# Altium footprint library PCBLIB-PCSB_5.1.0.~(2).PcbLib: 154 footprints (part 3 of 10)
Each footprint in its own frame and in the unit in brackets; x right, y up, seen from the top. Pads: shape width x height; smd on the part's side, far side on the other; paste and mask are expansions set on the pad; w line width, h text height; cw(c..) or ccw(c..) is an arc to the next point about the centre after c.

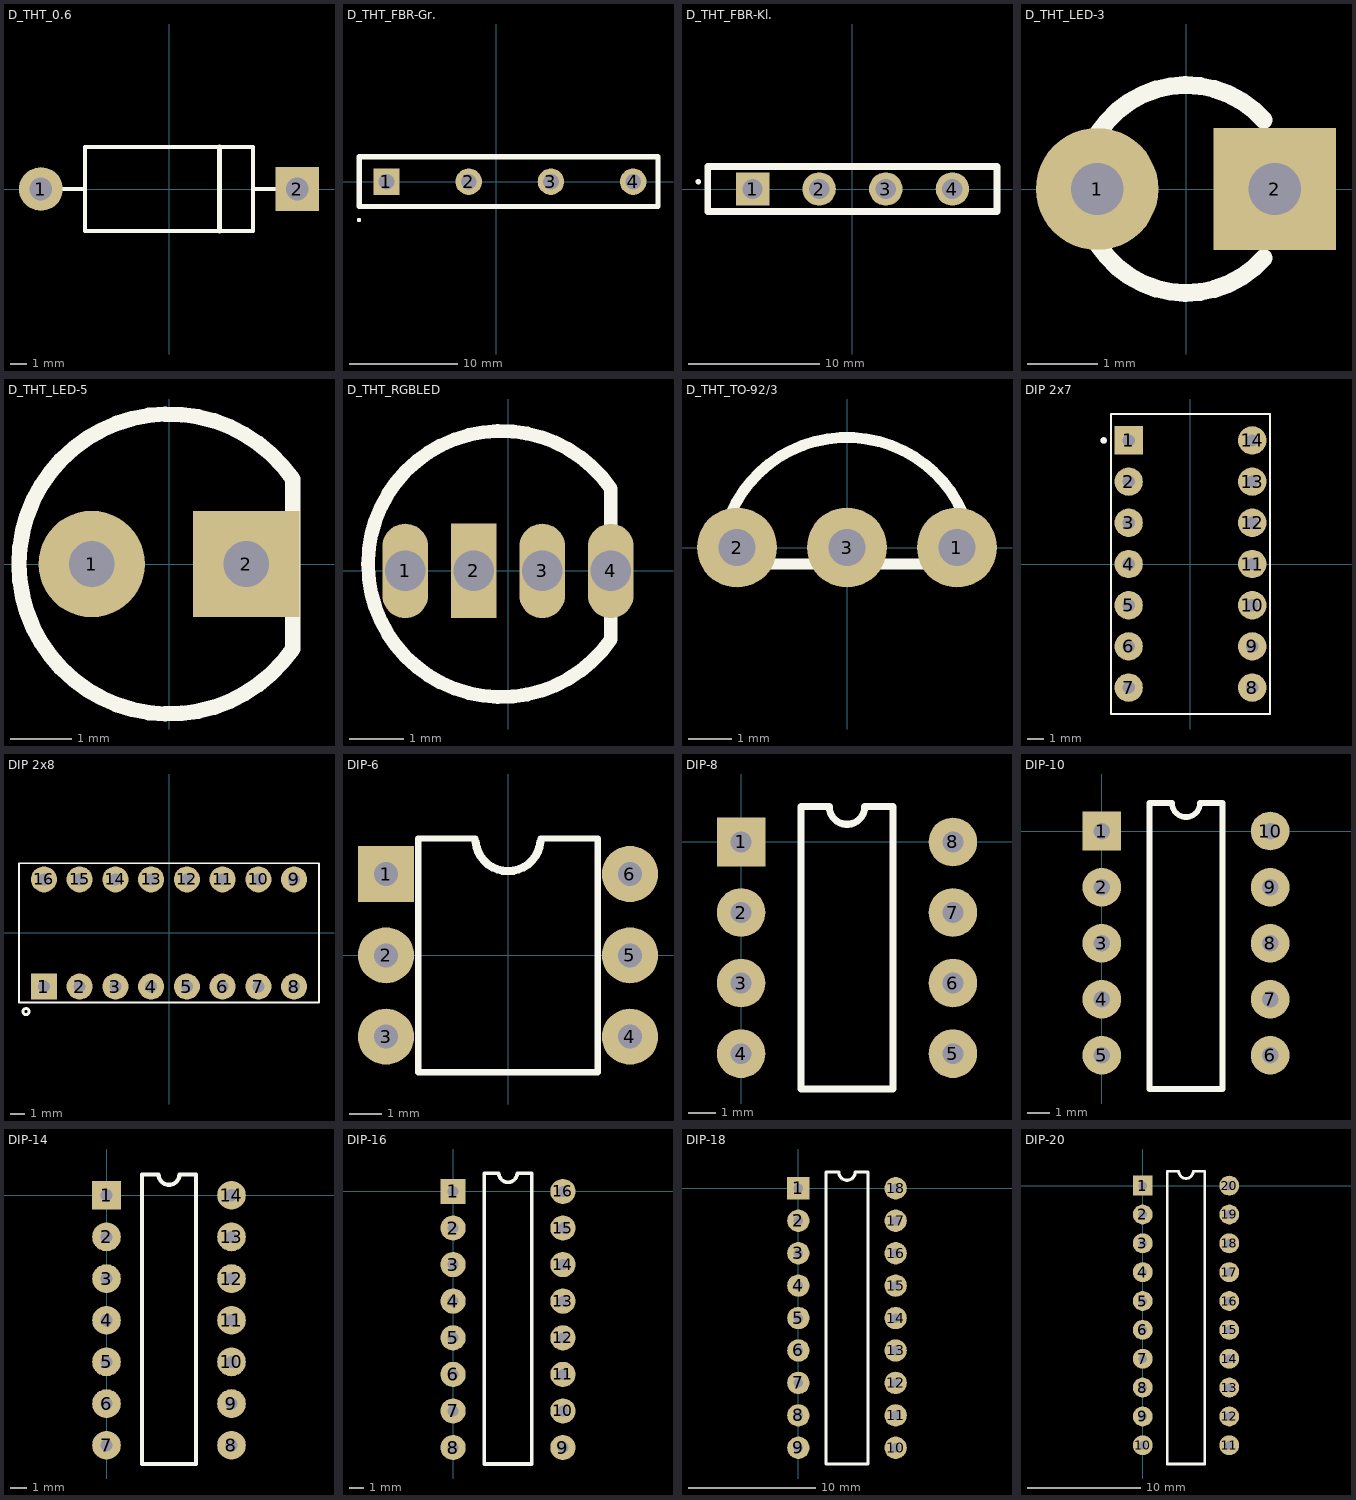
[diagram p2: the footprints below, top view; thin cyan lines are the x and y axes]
## D_THT_0.6 [mm] "LB-2024-04-17"
pads (2):
  round 2.6 hole 1.35: 1(-7.62,0)
  rect 2.6x2.6 hole 1.35: 2(7.62,0)
Top Overlay:
  lines w0.254: -7,0 -5,0 ; -5,-2.5 -5,2.5 5,2.5 5,-2.5 -4.89,-2.5 ; 5,0 7.016,0
  lines w0.3: 3,-2.5 3,2.5

## D_THT_FBR-Gr. [mm] "LB-2024-04-18"
height 23
pads (4):
  rect 2.45x2.45 hole 1.45: 1(-10.16,0)
  round 2.45 hole 1.45: 2(-2.54,0) 3(5.08,0) 4(12.7,0)
Top Overlay:
  circle w0.2: c-12.7,-3.556 r0.1
  lines w0.5: -12.7,-2.3 -12.7,2.3 15,2.3 15,-2.3 -12.7,-2.3

## D_THT_FBR-Kl. [mm] "LB-2024-04-18"
pads (4):
  rect 2.55x2.55 hole 1.55: 1(-7.62,0)
  round 2.55 hole 1.55: 2(-2.54,0) 3(2.54,0) 4(7.62,0)
Top Overlay:
  circle w0.2: c-11.76,0.56 r0.1
  lines w0.5: -9.095,1.715 -11.025,1.715 ; 9.095,1.715 11.025,1.715 ; -11.025,1.715 11.025,1.715 ; -11.025,1.715 -11.025,-1.715 11.025,-1.715 11.025,1.715
Mechanical 13:
  circle w0.2: c-11.76,0.56 r0.1

## D_THT_LED-3 [mm] "LB-2024-04-17"
pads (2):
  round 1.75 hole 0.75: 1(-1.27,0)
  rect 1.75x1.75 hole 0.75: 2(1.27,0)
Top Overlay:
  lines w0.254: 1.111,-0.988 cw(c0,0) 1.111,0.988 ; 1.397,-0.508 1.397,0.508

## D_THT_LED-5 [mm] "LB-2024-04-17"
pads (2):
  round 1.75 hole 0.75: 1(-1.27,0)
  rect 1.75x1.75 hole 0.75: 2(1.27,0)
Top Overlay:
  lines w0.254: 2.032,-1.397 cw(c0,0) 2.032,1.397 2.032,-1.397

## D_THT_RGBLED [mm] "LB-2024-04-17"
pads (4):
  oval 0.85x1.75 hole 0.75: 1(-1.905,0) 3(0.635,0) 4(1.905,0)
  rect 0.85x1.75 hole 0.75: 2(-0.635,0)
Top Overlay:
  lines w0.254: 1.905,-0.635 1.905,-1.27 cw(c-0.127,0.127) 1.905,1.524 1.905,0.635

## D_THT_TO-92/3 [mm] "LB-2024-04-19"
pads (3):
  round 1.85 hole 0.85: 1(2.54,0) 2(-2.54,0) 3(0,0)
Top Overlay:
  lines w0.254: -2.927,-0.381 cw(c-0.003,-0.381) 2.921,-0.381 -2.927,-0.381

## DIP 2x7 [mm] "LB-2024-04-19"
pads (14):
  rect 1.75x1.75 hole 0.75: 1(-3.81,7.62)
  round 1.75 hole 0.75: 2(-3.81,5.08) 3(-3.81,2.54) 4(-3.81,0) 5(-3.81,-2.54) 6(-3.81,-5.08) 7(-3.81,-7.62) 8(3.81,-7.62) 9(3.81,-5.08) 10(3.81,-2.54) 11(3.81,0) 12(3.81,2.54) 13(3.81,5.08) 14(3.81,7.62)
Top Overlay:
  circle w0.2: c-5.35,7.62 r0.1
  lines w0.127: -4.9,-7.92 -4.9,-9.25 ; -4.9,7.92 -4.9,9.25 ; 4.9,-7.92 4.9,-9.25 ; 4.9,7.92 4.9,9.25 ; -4.9,-9.25 -4.9,9.25 ; -4.9,-9.25 4.9,-9.25 ; -4.9,-9.25 4.9,-9.25 ; -4.9,9.25 4.9,9.25 ; -4.9,9.25 4.9,9.25 ; 4.9,-9.25 4.9,9.25
Mechanical 13:
  circle w0.2: c-5.35,7.62 r0.1

## DIP 2x8 [mm] "LB-2024-04-19"
pads (16):
  rect 1.85x1.85 hole 0.85: 1(-8.89,-3.81)
  round 1.85 hole 0.85: 2(-6.35,-3.81) 3(-3.81,-3.81) 4(-1.27,-3.81) 5(1.27,-3.81) 6(3.81,-3.81) 7(6.35,-3.81) 8(8.89,-3.81) 9(8.89,3.81) 10(6.35,3.81) 11(3.81,3.81) 12(1.27,3.81) 13(-1.27,3.81) 14(-3.81,3.81) 15(-6.35,3.81) 16(-8.89,3.81)
Top Overlay:
  circle w0.2: c-10.16,-5.588 r0.218
  lines w0.127: -10.66,-4.95 10.66,-4.95 10.66,4.95 -10.66,4.95 -10.66,-4.95

## DIP-6 [mm] "LB-2024-04-17"
pads (6):
  rect 1.75x1.75 hole 0.75: 1(-3.81,2.54)
  round 1.75 hole 0.75: 2(-3.81,0) 3(-3.81,-2.54) 4(3.81,-2.54) 5(3.81,0) 6(3.81,2.54)
Top Overlay:
  lines w0.2: -1.016,3.65 -2.8,3.65 -2.8,-3.65 2.8,-3.65 2.8,3.65 1.016,3.65
  lines w0.254: -1.016,3.556 ccw(c0,3.65) 1.016,3.556

## DIP-8 [mm] "LB-2024-04-17"
pads (8):
  rect 1.75x1.75 hole 0.75: 1(0,0)
  round 1.75 hole 0.75: 2(0,-2.54) 3(0,-5.08) 4(0,-7.62) 5(7.62,-7.62) 6(7.62,-5.08) 7(7.62,-2.54) 8(7.62,0)
Top Overlay:
  lines w0.254: 2.159,-8.89 2.159,1.27 3.175,1.27 ccw(c3.81,1.27) 4.445,1.27 5.461,1.27 5.461,-8.89 2.159,-8.89

## DIP-10 [mm] "LB-2024-04-17"
pads (10):
  rect 1.75x1.75 hole 0.75: 1(0,0)
  round 1.75 hole 0.75: 2(0,-2.54) 3(0,-5.08) 4(0,-7.62) 5(0,-10.16) 6(7.62,-10.16) 7(7.62,-7.62) 8(7.62,-5.08) 9(7.62,-2.54) 10(7.62,0)
Top Overlay:
  lines w0.254: 2.159,-11.684 2.159,1.27 3.175,1.27 ccw(c3.81,1.27) 4.445,1.27 5.461,1.27 5.461,-11.684 2.159,-11.684

## DIP-14 [mm] "LB-2024-04-17"
pads (14):
  rect 1.75x1.75 hole 0.75: 1(0,0)
  round 1.75 hole 0.75: 2(0,-2.54) 3(0,-5.08) 4(0,-7.62) 5(0,-10.16) 6(0,-12.7) 7(0,-15.24) 8(7.62,-15.24) 9(7.62,-12.7) 10(7.62,-10.16) 11(7.62,-7.62) 12(7.62,-5.08) 13(7.62,-2.54) 14(7.62,0)
Top Overlay:
  lines w0.254: 2.159,-16.383 5.461,-16.383 5.461,1.27 4.445,1.27 cw(c3.81,1.27) 3.175,1.27 2.159,1.27 2.159,-16.383

## DIP-16 [mm] "LB-2024-04-17"
pads (16):
  rect 1.75x1.75 hole 0.75: 1(0,0)
  round 1.75 hole 0.75: 2(0,-2.54) 3(0,-5.08) 4(0,-7.62) 5(0,-10.16) 6(0,-12.7) 7(0,-15.24) 8(0,-17.78) 9(7.62,-17.78) 10(7.62,-15.24) 11(7.62,-12.7) 12(7.62,-10.16) 13(7.62,-7.62) 14(7.62,-5.08) 15(7.62,-2.54) 16(7.62,0)
Top Overlay:
  lines w0.254: 2.159,-18.923 2.159,1.27 3.175,1.27 ccw(c3.81,1.27) 4.445,1.27 5.461,1.27 5.461,-18.923 2.159,-18.923

## DIP-18 [mm] "LB-2024-04-17"
pads (18):
  rect 1.75x1.75 hole 0.75: 1(0,0)
  round 1.75 hole 0.75: 2(0,-2.54) 3(0,-5.08) 4(0,-7.62) 5(0,-10.16) 6(0,-12.7) 7(0,-15.24) 8(0,-17.78) 9(0,-20.32) 10(7.62,-20.32) 11(7.62,-17.78) 12(7.62,-15.24) 13(7.62,-12.7) 14(7.62,-10.16) 15(7.62,-7.62) 16(7.62,-5.08) 17(7.62,-2.54) 18(7.62,0)
Top Overlay:
  lines w0.254: 2.159,-21.59 5.461,-21.59 5.461,1.27 4.445,1.27 cw(c3.81,1.27) 3.175,1.27 2.159,1.27 2.159,-21.59

## DIP-20 [mm] "LB-2024-04-17"
pads (20):
  rect 1.75x1.75 hole 0.75: 1(0,0)
  round 1.75 hole 0.75: 2(0,-2.54) 3(0,-5.08) 4(0,-7.62) 5(0,-10.16) 6(0,-12.7) 7(0,-15.24) 8(0,-17.78) 9(0,-20.32) 10(0,-22.86) 11(7.62,-22.86) 12(7.62,-20.32) 13(7.62,-17.78) 14(7.62,-15.24) 15(7.62,-12.7) 16(7.62,-10.16) 17(7.62,-7.62) 18(7.62,-5.08) 19(7.62,-2.54) 20(7.62,0)
Top Overlay:
  lines w0.254: 2.159,-24.511 2.159,1.27 3.175,1.27 ccw(c3.81,1.27) 4.445,1.27 5.461,1.27 5.461,-24.511 2.159,-24.511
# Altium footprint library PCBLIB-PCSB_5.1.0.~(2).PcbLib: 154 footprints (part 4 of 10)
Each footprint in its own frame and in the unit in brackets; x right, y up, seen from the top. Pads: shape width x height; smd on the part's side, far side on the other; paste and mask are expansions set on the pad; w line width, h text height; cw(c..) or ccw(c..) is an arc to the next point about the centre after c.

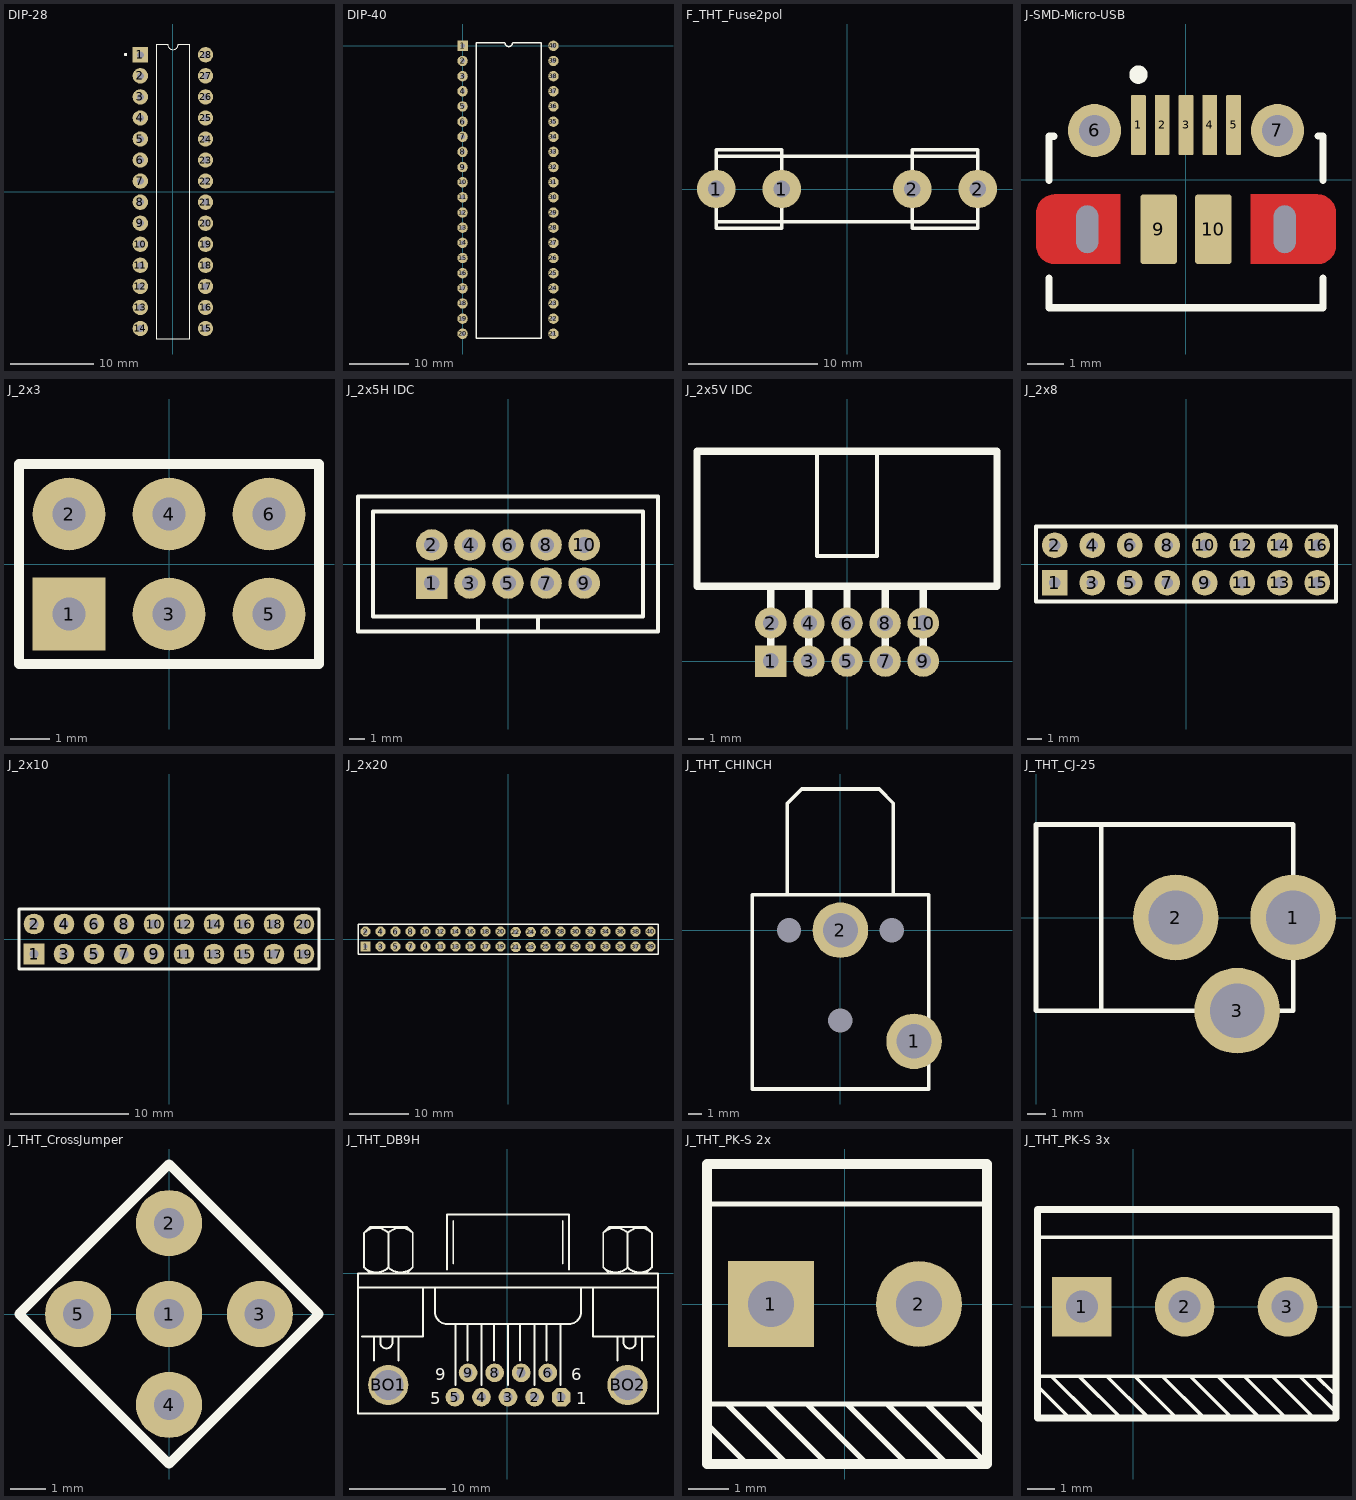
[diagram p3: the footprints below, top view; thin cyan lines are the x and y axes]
## DIP-28 [mm] "LB-2024-04-17"
pads (28):
  rect 1.85x1.85 hole 0.85: 1(-3.935,16.51)
  round 1.85 hole 0.85: 2(-3.935,13.97) 3(-3.935,11.43) 4(-3.935,8.89) 5(-3.935,6.35) 6(-3.935,3.81) 7(-3.935,1.27) 8(-3.935,-1.27) 9(-3.935,-3.81) 10(-3.935,-6.35) 11(-3.935,-8.89) 12(-3.935,-11.43) 13(-3.935,-13.97) 14(-3.935,-16.51) 15(3.935,-16.51) 16(3.935,-13.97) 17(3.935,-11.43) 18(3.935,-8.89) 19(3.935,-6.35) 20(3.935,-3.81) 21(3.935,-1.27) 22(3.935,1.27) 23(3.935,3.81) 24(3.935,6.35) 25(3.935,8.89) 26(3.935,11.43) 27(3.935,13.97) 28(3.935,16.51)
Top Overlay:
  circle w0.2: c-5.714,16.544 r0.1
  lines w0.14: -0.66,17.78 -1,17.78 -2,17.78 -2,-17.78 2,-17.78 2,17.78 ; -0.635,17.78 ccw(c0,17.78) 0.635,17.78 ; 0.642,17.78 1.642,17.78 1.981,17.78
Mechanical 13:
  circle w0.2: c-5.714,16.544 r0.1

## DIP-40 [mm] "LB-2024-04-17"
pads (40):
  rect 1.75x1.75 hole 0.75: 1(0,0)
  round 1.75 hole 0.75: 2(0,-2.54) 3(0,-5.08) 4(0,-7.62) 5(0,-10.16) 6(0,-12.7) 7(0,-15.24) 8(0,-17.78) 9(0,-20.32) 10(0,-22.86) 11(0,-25.4) 12(0,-27.94) 13(0,-30.48) 14(0,-33.02) 15(0,-35.56) 16(0,-38.1) 17(0,-40.64) 18(0,-43.18) 19(0,-45.72) 20(0,-48.26) 21(15.24,-48.26) 22(15.24,-45.72) 23(15.24,-43.18) 24(15.24,-40.64) 25(15.24,-38.1) 26(15.24,-35.56) 27(15.24,-33.02) 28(15.24,-30.48) 29(15.24,-27.94) 30(15.24,-25.4) 31(15.24,-22.86) 32(15.24,-20.32) 33(15.24,-17.78) 34(15.24,-15.24) 35(15.24,-12.7) 36(15.24,-10.16) 37(15.24,-7.62) 38(15.24,-5.08) 39(15.24,-2.54) 40(15.24,0)
Top Overlay:
  lines w0.254: 2.286,-49.022 13.208,-49.022 13.208,0.508 8.382,0.508 cw(c7.747,0.508) 7.112,0.508 2.286,0.508 2.286,-49.022

## F_THT_Fuse2pol [mm] "LB-2024-04-17"
pads (4):
  round 3 hole 1.3: 1(-10.163,0.008) 1(-5.083,0.008) 2(5.077,0.008) 2(10.157,0.008)
Top Overlay:
  lines w0.254: -10.163,-2.532 -10.163,-3.04 -5.083,-3.04 -5.083,-2.532 -5.083,2.548 -5.083,3.056 -10.163,3.056 -10.163,2.548 ; -10.163,-2.532 10.157,-2.532 ; -10.163,-2.532 -10.163,2.548 ; -10.163,2.548 10.157,2.548 ; 10.157,-2.532 10.157,-3.04 5.077,-3.04 5.077,-2.532 5.077,2.548 5.077,3.056 10.157,3.056 10.157,2.548 ; 10.157,-2.532 10.157,2.548

## J-SMD-Micro-USB [mm] "LB-2024-04-18"
height 2.673
pads (11):
  rrect15% 0.4x1.65 smd paste-0.02 mask+0.05: 1(-1.3,1.5) 2(-0.65,1.5) 3(0,1.5) 4(0.65,1.5) 5(1.3,1.5)
  round 1.45 hole 0.85: 6(-2.5,1.35) 7(2.5,1.35)
  rrect50% 0x0 hole 0.6 slot 1.3 at 90 deg: 8(-2.7,-1.35) 11(2.7,-1.35)
  rrect15% 1x1.9 smd paste-0.02 mask+0.05: 9(-0.75,-1.35) 10(0.75,-1.35)
Top Layer:
  circle w0.5: c-3.6,-1.8 r0.25
  circle w0.5: c-3.6,-0.9 r0.25
  circle w0.5: c3.6,-1.8 r0.25
  circle w0.5: c3.6,-0.9 r0.25
  region: -1.8,-2.3 -1.8,-0.4 -3.6,-0.4 -3.6,-2.3
  region: -3.6,-1.8 -3.6,-0.9 -4.1,-0.9 -4.1,-1.8
  region: 1.775,-0.4 1.775,-2.3 3.6,-2.3 3.6,-0.4
  region: 3.6,-0.9 3.6,-1.8 4.1,-1.8 4.1,-0.9
Top Overlay:
  circle w0.25: c-1.3,2.875 r0.125
  lines w0.2: -3.745,-2.688 -3.745,-3.5 3.745,-3.5 3.745,-2.688 ; -3.745,-0.012 -3.745,1.195 -3.614,1.195 ; 3.615,1.2 3.745,1.2 3.745,-0.012

## J_2x3 [mm] "LB-2024-04-19"
pads (6):
  rect 1.85x1.85 hole 0.85 mask+0.102: 1(-2.54,-1.27)
  round 1.85 hole 0.85 mask+0.102: 2(-2.54,1.27) 3(0,-1.27) 4(0,1.27) 5(2.54,-1.27) 6(2.54,1.27)
Top Overlay:
  lines w0.254: -3.81,-2.54 -3.81,2.54 3.81,2.54 3.81,-2.54 -3.81,-2.54

## J_2x5H IDC [mm] "LB-2024-04-19"
height 9
pads (10):
  rect 2.1x2.1 hole 1.05 mask+0.102: 1(-5.08,-1.27)
  round 2.1 hole 1.05 mask+0.102: 2(-5.08,1.27) 3(-2.54,-1.27) 4(-2.54,1.27) 5(0,-1.27) 6(0,1.27) 7(2.54,-1.27) 8(2.54,1.27) 9(5.08,-1.27) 10(5.08,1.27)
Top Overlay:
  lines w0.254: -2,-4.5 -2,-3.5 ; -0.5,4.5 10,4.5 10,-4.5 -10,-4.5 -10,4.5 0,4.5 ; 2,-4.5 2,-3.5 ; -9,-3.5 -9,3.5 9,3.5 9,-3.5 -9,-3.5

## J_2x5V IDC [mm] "LB-2024-04-19"
height 9
pads (10):
  rect 2.1x2.1 hole 1.05 mask+0.102: 1(-5.08,0)
  round 2.1 hole 1.05 mask+0.102: 2(-5.08,2.54) 3(-2.54,0) 4(-2.54,2.54) 5(0,0) 6(0,2.54) 7(2.54,0) 8(2.54,2.54) 9(5.08,0) 10(5.08,2.54)
Top Overlay:
  lines w0.254: -2,14 -2,7 2,7 2,14
  lines w0.5: -5.08,0 -5.08,5 ; -2.54,0 -2.54,5 ; 0,0 0,5 ; 2.54,0 2.54,5 ; 5.08,0 5.08,5 ; 0,5 -10,5 -10,14 10,14 10,5 0,5

## J_2x8 [mm] "LB-2024-04-19"
pads (16):
  rect 1.75x1.75 hole 0.75: 1(-8.89,-1.27)
  round 1.75 hole 0.75: 2(-8.89,1.27) 3(-6.35,-1.27) 4(-6.35,1.27) 5(-3.81,-1.27) 6(-3.81,1.27) 7(-1.27,-1.27) 8(-1.27,1.27) 9(1.27,-1.27) 10(1.27,1.27) 11(3.81,-1.27) 12(3.81,1.27) 13(6.35,-1.27) 14(6.35,1.27) 15(8.89,-1.27) 16(8.89,1.27)
Top Overlay:
  lines w0.254: -10.16,-2.54 -10.16,2.54 10.16,2.54 10.16,-2.54 -10.16,-2.54

## J_2x10 [mm] "LB-2024-4-19"
pads (20):
  rect 1.75x1.75 hole 0.75: 1(-11.43,-1.27)
  round 1.75 hole 0.75: 2(-11.43,1.27) 3(-8.89,-1.27) 4(-8.89,1.27) 5(-6.35,-1.27) 6(-6.35,1.27) 7(-3.81,-1.27) 8(-3.81,1.27) 9(-1.27,-1.27) 10(-1.27,1.27) 11(1.27,-1.27) 12(1.27,1.27) 13(3.81,-1.27) 14(3.81,1.27) 15(6.35,-1.27) 16(6.35,1.27) 17(8.89,-1.27) 18(8.89,1.27) 19(11.43,-1.27) 20(11.43,1.27)
Top Overlay:
  lines w0.254: -12.7,-2.54 -12.7,2.54 12.7,2.54 12.7,-2.54 -12.7,-2.54

## J_2x20 [mm] "LB-2024-4-19"
pads (40):
  rect 1.75x1.75 hole 0.75: 1(-24.13,-1.224)
  round 1.75 hole 0.75: 2(-24.13,1.316) 3(-21.59,-1.224) 4(-21.59,1.316) 5(-19.05,-1.224) 6(-19.05,1.316) 7(-16.51,-1.224) 8(-16.51,1.316) 9(-13.97,-1.224) 10(-13.97,1.316) 11(-11.43,-1.224) 12(-11.43,1.316) 13(-8.89,-1.224) 14(-8.89,1.316) 15(-6.35,-1.224) 16(-6.35,1.316) 17(-3.81,-1.224) 18(-3.81,1.316) 19(-1.27,-1.224) 20(-1.27,1.316) 21(1.296,-1.316) 22(1.296,1.224) 23(3.836,-1.316) 24(3.836,1.224) 25(6.35,-1.224) 26(6.35,1.316) 27(8.89,-1.224) 28(8.89,1.316) 29(11.43,-1.224) 30(11.43,1.316) 31(13.97,-1.224) 32(13.97,1.316) 33(16.51,-1.224) 34(16.51,1.316) 35(19.05,-1.224) 36(19.05,1.316) 37(21.59,-1.224) 38(21.59,1.316) 39(24.13,-1.224) 40(24.13,1.316)
Top Overlay:
  lines w0.254: -25.4,-2.494 25.4,-2.494 25.4,2.586 -25.4,2.586 -25.4,-2.494

## J_THT_CHINCH [mm] "LB-2024-04-19"
pads (5):
  round 4 hole 2.5: 1(5.3,-8) 2(0,0)
  round 0.5 hole 1.75: 3(-3.7,0) 3(0,-6.5) 3(3.7,0)
Top Overlay:
  lines w0.254: -3.81,2.54 -3.81,9.144 -2.794,10.16 2.794,10.16 3.81,9.144 3.81,2.54 ; -6.35,-11.43 -6.35,2.54 -5.08,2.54 5.08,2.54 6.35,2.54 6.35,-11.43 -6.35,-11.43

## J_THT_CJ-25 [mm] "LB-2024-04-19"
height 1.7
pads (3):
  round 4.6 hole 2.9: 1(13.8,0) 2(7.5,0) 3(10.8,-5)
Top Overlay:
  lines w0.254: 3.5,-5 3.5,5 ; 0,-5 0,5 13.8,5 13.8,-5 0,-5

## J_THT_CrossJumper [mm] "LB-2024-04-19"
pads (5):
  round 1.85 hole 0.85: 1(0,0) 2(0,2.54) 3(2.54,0) 4(0,-2.54) 5(-2.54,0)
Top Overlay:
  lines w0.254: -4.191,0 0,-4.191 4.191,0 0,4.191 -4.191,0

## J_THT_DB9H [mm] "LB-2024-04-17"
pads (11):
  oct 1.95x1.95 hole 0.95: 1(5.6,-12.937)
  round 1.95 hole 0.95: 2(2.827,-12.937) 3(0.054,-12.937) 4(-2.718,-12.937) 5(-5.491,-12.937) 6(4.203,-10.397) 7(1.43,-10.397) 8(-1.343,-10.397) 9(-4.115,-10.397)
  round 4.2 hole 3.15: BO1(-12.455,-11.667) BO2(12.543,-11.667)
Top Overlay:
  lines w0.203: -15.609,-1.507 15.718,-1.507 ; -15.186,-6.587 -8.836,-6.587 -8.836,-1.507 ; -14.976,0.608 ccw(c-13.704,1.88) -12.432,0.608 ; -14.976,4.211 cw(c-13.704,2.938) -12.432,4.211 ; -14.339,-0.025 -14.974,0.61 -14.974,4.208 -14.339,4.843 -10.529,4.843 -9.894,4.208 -9.894,0.61 -10.529,-0.025 ; -13.916,-9.127 -13.916,-6.587 ; -13.281,-6.587 -13.281,-7.222 ccw(c-12.646,-7.222) -12.011,-7.222 -12.011,-6.587 ; -12.436,0.608 ccw(c-11.164,1.88) -9.892,0.608 ; -12.436,4.211 cw(c-11.164,2.938) -9.892,4.211 ; -12.434,0.61 -12.434,4.208 ; -11.376,-9.127 -11.376,-6.587 ; -7.566,-1.507 -7.566,-4.047 ccw(c-6.296,-4.047) -6.296,-5.317 6.404,-5.317 ccw(c6.404,-4.047) 7.674,-4.047 7.674,-1.507 ; -6.296,0.398 -6.296,6.113 6.404,6.113 6.404,0.398 ; -5.661,1.033 -5.661,5.478 ; -5.449,-11.667 -5.449,-5.317 ; -4.179,-9.127 -4.179,-5.317 ; -2.697,-11.667 -2.697,-5.317 ; -1.427,-9.127 -1.427,-5.317 ; 0.054,-11.667 0.054,-5.317 ; 1.324,-9.127 1.324,-5.317 ; 2.806,-11.667 2.806,-5.317 ; 4.076,-9.127 4.076,-8.915 4.076,-5.317 ; 5.558,-11.667 5.558,-5.317 ; 5.769,1.033 5.769,5.478 ; 8.944,-1.507 8.944,-6.587 15.294,-6.587 ; 10,0.608 ccw(c11.273,1.88) 12.545,0.608 ; 10,4.211 cw(c11.273,2.938) 12.545,4.211 ; 10.638,-0.025 10.003,0.61 10.003,4.208 10.638,4.843 14.448,4.843 15.083,4.208 15.083,0.61 14.448,-0.025 ; 11.484,-9.127 11.484,-6.587 ; 12.119,-6.587 12.119,-7.222 ccw(c12.754,-7.222) 13.389,-7.222 13.389,-6.587 ; 12.54,0.608 ccw(c13.813,1.88) 15.085,0.608 ; 12.54,4.211 cw(c13.813,2.938) 15.085,4.211 ; 12.543,0.61 12.543,4.208 ; 14.024,-9.127 14.024,-6.587 ; -15.609,-14.63 -15.609,-0.025 15.718,-0.025 15.718,-14.63 -15.609,-14.63
  text "9" at -7.566,-11.159 h1.27
  text "5" at -8.074,-13.699 h1.27
  text "1" at 7.166,-13.699 h1.27
  text "6" at 6.658,-11.159 h1.27

## J_THT_PK-S 2x [mm] "LB-2024-05-03g"
pads (2):
  rect 2.15x2.15 hole 1.15: 1(-1.85,0)
  round 2.15 hole 1.15: 2(1.85,0)
Top Overlay:
  lines w0.127: -3.45,2.5 3.55,2.5 ; -2.45,-4 -3.45,-3 -3.45,-2.5 3.55,-2.5 ; -1.95,-2.5 -0.45,-4 ; -1.45,-4 -2.95,-2.5 ; -0.95,-2.5 0.55,-4 ; 0.05,-2.5 1.55,-4 ; 1.05,-2.5 2.55,-4 ; 3.55,-4 2.05,-2.5 ; 3.55,-3 3.05,-2.5 ; -2.95,-2.5 -2.95,-2.5 ; 2.05,-2.5 2.05,-2.5 ; 3.05,-2.5 3.05,-2.5 ; 3.05,-2.5 3.05,-2.5
  lines w0.254: -3.45,-4 -2.91,-4 3.55,-4 3.55,3.5 -3.45,3.5 -3.45,2.365 -3.45,-4

## J_THT_PK-S 3x [mm] "LB-2024-05-03g"
pads (3):
  rect 2.15x2.15 hole 1.15: 1(-1.85,0)
  round 2.15 hole 1.15: 2(1.85,0) 3(5.55,0)
Top Overlay:
  lines w0.127: -3.5,-2.5 6.5,-2.5 7.3,-2.5 ; -3.45,2.5 7.3,2.5 ; -3.4,-2.9 -2.3,-4 ; -1.95,-2.5 -0.45,-4 ; -1.45,-4 -2.95,-2.5 ; -0.95,-2.5 0.55,-4 ; 0.05,-2.5 1.55,-4 ; 1.05,-2.5 2.55,-4 ; 3.55,-4 2.05,-2.5 ; 4,-2.5 5.425,-3.925 ; 4.575,-4.025 3.05,-2.5 ; 5,-2.5 6.5,-4 ; 6,-2.5 7.3,-3.8 ; 7,-2.5 6.6,-2.5 7.25,-3.15 ; -2.95,-2.5 -2.95,-2.5 ; 2.05,-2.5 2.05,-2.5 ; 3.05,-2.5 3.05,-2.5 ; 3.05,-2.5 3.05,-2.5
  lines w0.254: -3.45,-4 -2.91,-4 3.55,-4 7.3,-4 7.3,3.5 -3.45,3.5 -3.45,2.365 -3.45,-4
